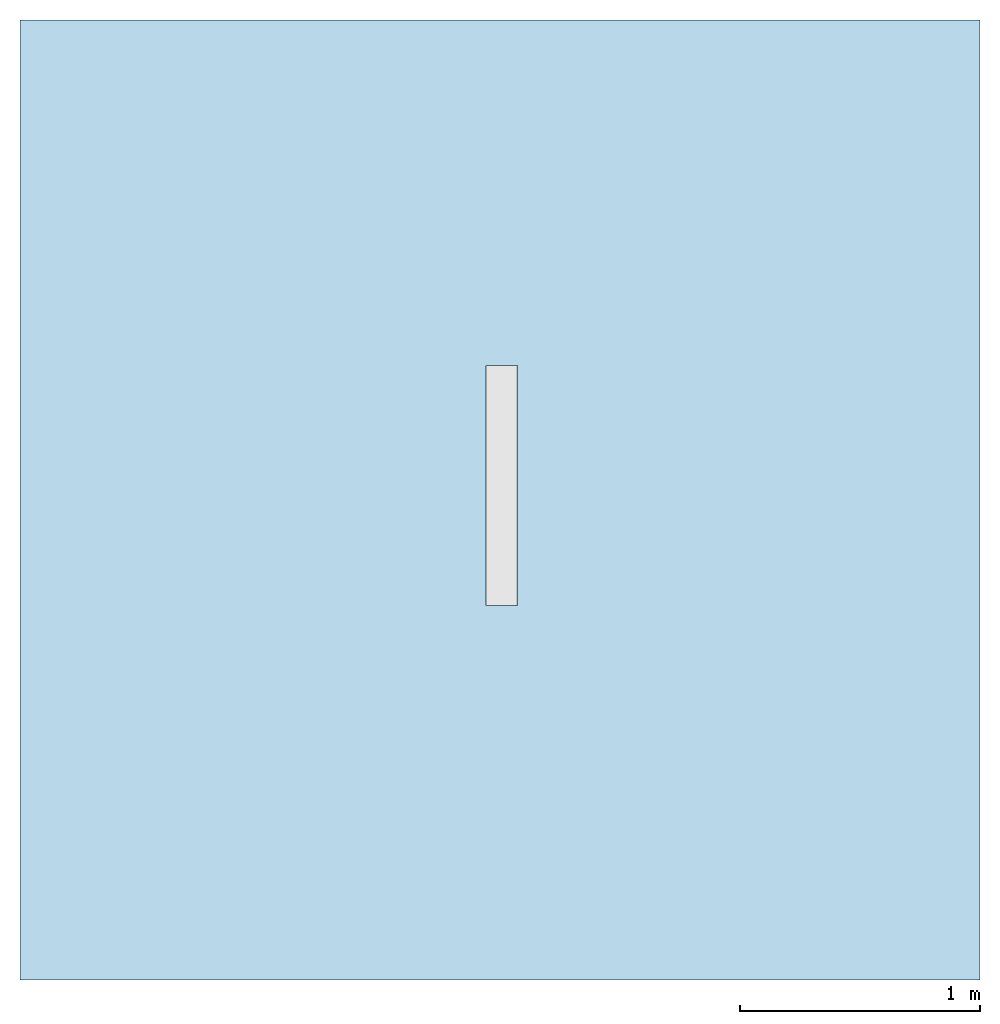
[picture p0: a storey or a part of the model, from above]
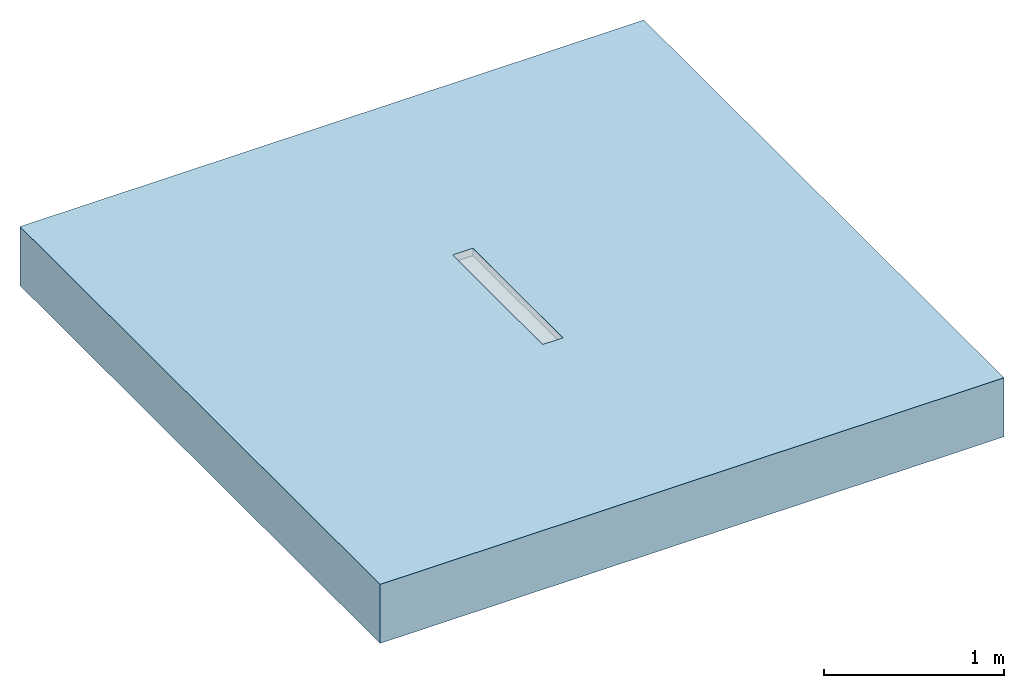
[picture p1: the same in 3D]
Properties of the parts of a building model (IFC2X3)

# File
Description: ViewDefinition [CoordinationView]
File name: Project Number
Time: 2014-06-06T15:09:12
Written by: The EXPRESS Data Manager Version 5.01.0100.02.64mod : 6 Jun 2012
Made in: 20130308_1515(x64) - Exporter 2014.0.2013.0308 - Default UI
Comment: STEP Physical File produced by: The EXPRESS Data Manager Version 5.01.0100.02.64mod : 6 Jun 2012 * Module: EDMstepFileFactory/EDMstandAlone * Creation date: Fri Jun 06 15:09:12 2014 * Host: IN-BLR-PC-0010 * Database: C:\Users\palleri\AppData\Local\Temp\{E43DC658-EC8C-4075-AFD4-A7E245FBBFBA}\ifc * Database version: 5507 * Database creation date: Fri Jun 06 15:09:11 2014 * Schema: IFC2X3 * Model: DataRepository.ifc * Model creation date: Fri Jun 06 15:09:11 2014 * Header model: DataRepository.ifc_HeaderModel * Header model creation date: Fri Jun 06 15:09:11 2014 * EDMuser: sdai-user * EDMgroup: sdai-group * License ID and type: 5605 : Permanent license. Expiry date: * EDMstepFileFactory options: 020000

# IfcProject, Project Number
LongName: Project Name; Phase: Project Status

# IfcSite, Default
RefLatitude: 42, 21, 30, 344238; RefLongitude: -71, -3, -35, -194702; RefElevation: 0 mm

# IfcBuilding
Pset_BuildingCommon - NumberOfStoreys: 1
Other - Client Name: Owner; Project Address: ## Street City, State Zip; Project Status: Project Status; Project Name: Project Name; Project Number: Project Number; Project Issue Date: Issue Date

# IfcBuildingStorey, Level 1
LongName: Level 1; Elevation: 0 mm
Constraints - Elevation Base: Project Base Point; Elevation: 0 mm
Graphics - Line Pattern: Center; Symbol at End 1 Default: no; Color: 0; Symbol at End 2 Default: yes; Line Weight: 1; Symbol: M_Level Head - Circle: M_Level Head - Circle
Dimensions - Computation Height: 0 mm
Identity Data - Name: Level 1; Structural: no; Building Story: yes

# IfcFlowTerminal: 38146 - Fixed Height Channel - Shallow Section - 1000mm LG - Invert Depth 50mm, ACO Freedeck Fixed Height Channel Shallow Section - Galvanized Steel:38146 - Fixed Height Channel - Shallow Section - 1000mm LG - Invert Depth 50mm:308688
In: Level 1
Material: Galvanized Steel
Construction - 00272 - Grating - Slotted Grating - Stainless Steel 304 - 1000mm long: no; 36955 - Grating - Plain Mesh - Stainless Steel 304 - 1000mm long: no; End Plate Invert 1: no; 00276 - Grating - Slotted Grating - Galvanised Steel - 1000mm long: no; End Plate Invert 2: no; 00273 - Grating - Slotted Grating - Stainless Steel 304 - 500mm long: no; 36954 - Grating - Plain Mesh - Stainless Steel 304 - 500mm long: no; 00277 - Grating - Slotted Grating - Galvanised Steel - 500mm long: no; 36952 - Grating - Plain Mesh - Galvanised Steel - 500mm long: no; 36953 - Grating - Plain Mesh - Galvanised Steel - 1000mm long: yes
Constraints - Moves With Nearby Elements: no; Level: Level: Level 1
Identity Data - Mark: 28; Telephone: +44 (0)1462 816666; Watermarked By: www.acobd.com; Manufacturer: ACO Building Drainage; Watermark1: This file is the property of ACO Technologies PLC; Watermarked With: BIM Manager Premium Suite; Fax: +44 (0)1462 851490; E-mail Sales: abdcommercial@aco.co.uk; Address: ACO Business Centre, Caxton Road, Bedford, MK41 0LF; Watermark2: This file is water marked and users are prohibited to reproduce, adapt, distribute this information; Website: www.acobd.com; E-mail Technical: abdtechnical@aco.co.uk
Phasing - Phase Created: New Construction
Pset_ManufacturerTypeInformation - Manufacturer: ACO Building Drainage
General - Load Class: A15; Channel Recycled Material Content: 25 - 30 %; Channel Material: Hot Dipped Galvanised Steel; Price: POA - contact ACO; Installation Guidelines: X:\Electronic Literature\ABD Electronic Literature\Roof and Balcony Drainage\ACO Freedeck Brochure.pdf; Product Range: ACO Freedeck; Channel Recyclable: Fully recyclable; Product Standard: BS EN 1433:2002, CE marked; Weight (Kg): 2.0kg; Maintenance Guidelines: X:\Electronic Literature\ABD Electronic Literature\Roof and Balcony Drainage\ACO Freedeck Brochure.pdf; Dimensions (LxWxH): 1000 x 130 x 50; Product Code: 38146; Channel Colour: Galvanised; Product Type: Linear Deck Drainage System; Product Description: ACO FreeDeck Fixed Height Channel - Shallow Section; NBS Specification: NBS Section R10 Gravity Rainwater Drainage Systems, Subsection 365
Other - Nos: 32
Model Properties - Grating Product Code 36953: Load Class A15 - Mesh Grating - 14mm x 30mm Mesh - Galvanized Steel - 1000mm long - 3.0kg; Grating Product Code 00276: Load Class A15 - Slotted Grating - 10 x 80mm Slot - Galvanized Steel - 1000mm long - 2.2kg; End Plate Product Code 38148: End Plate - Galvanized Steel for Invert Depth - 50mm - 0.1Kg; Grating Product Code 00277: Load Class A15 - Slotted Grating - 10 x 80mm Slot - Galvanized Steel - 500mm long - 1.0kg; Grating Product Code 36952: Load Class A15 - Mesh Grating - 14mm x 30mm Mesh - Galvanized Steel - 500mm long - 1.6kg
Dimensions - Channel End Length: -1000 mm; Height: 50 mm; Grating End Length: 1000 mm
Materials and Finishes - Material: Galvanized Steel

# IfcSlab: Floor:Generic Floor - 400mm, Floor:Generic Floor - 400mm:193825
In: Level 1
PredefinedType: FLOOR; Material: Concrete, Broom Finish 400 mm
Constraints - Height Offset From Level: 0 mm; Related to Mass: no; Level: Level: Level 1; Room Bounding: yes
Dimensions - Area: 16 m2; Volume: 6.3935 m3; Perimeter: 16000 mm; Thickness: 400 mm
Structural - Enable Analytical Model: no; Structural: no
Phasing - Phase Created: New Construction
Pset_SlabCommon - Reference: Generic Floor - 400mm; IsExternal: no; LoadBearing: yes; ThermalTransmittance: 2.615 kg/K/s3; PitchAngle: 0 deg
Analytical Properties - Heat Transfer Coefficient (U): 2.615; Absorptance: 0.1; Thermal Resistance (R): 0.382409; Roughness: 1; Thermal mass: 604440
Graphics - Coarse Scale Fill Color: 0
Construction - Default Thickness: 400 mm; Function: Interior
Materials and Finishes - Structural Material: Concrete, Broom Finish
